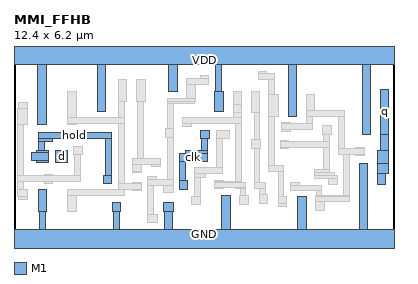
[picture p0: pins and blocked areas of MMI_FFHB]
MACRO MMI_FFHB
	CLASS CORE ;
	FOREIGN MMI_FFHB 0 0 ;
	SIZE 12.4 BY 6.2 ;
	SYMMETRY X Y ;
	SITE CORE1 ;
	PIN d
		DIRECTION input ;
		USE SIGNAL ;
		PORT
			LAYER M1 ;
			RECT 1.36 2.6 1.74 2.98 ;
		END
		AntennaGateArea 0.3465 ;
	END d
	PIN GND
		DIRECTION inout ;
		USE GROUND ;
		PORT
			LAYER M1 ;
			RECT 0.785 1 1.065 1.7 ;
			LAYER M1 ;
			RECT 3.21 1.005 3.49 1.285 ;
			LAYER M1 ;
			RECT 4.875 1.01 5.19 1.29 ;
			LAYER M1 ;
			RECT 0.83 0.42 1.025 1 ;
			LAYER M1 ;
			RECT 3.245 0.42 3.44 1.005 ;
			LAYER M1 ;
			RECT 4.9 0.42 5.18 1.01 ;
			LAYER M1 ;
			RECT 6.78 0.42 7.06 1.53 ;
			LAYER M1 ;
			RECT 9.26 0.42 9.54 1.47 ;
			LAYER M1 ;
			RECT 11.265 0.42 11.545 2.575 ;
			LAYER M1 ;
			RECT 0 -0.42 12.4 0.42 ;
		END
	END GND
	PIN q
		DIRECTION output ;
		USE SIGNAL ;
		PORT
			LAYER M1 ;
			RECT 11.95 3.515 12.23 4.985 ;
			LAYER M1 ;
			RECT 11.955 2.975 12.23 3.515 ;
			LAYER M1 ;
			RECT 11.86 2.575 12.23 2.975 ;
			LAYER M1 ;
			RECT 11.855 2.24 12.23 2.575 ;
			LAYER M1 ;
			RECT 11.855 1.875 12.135 2.24 ;
		END
		AntennaDiffArea 0.91245 ;
	END q
	PIN VDD
		DIRECTION inout ;
		USE POWER ;
		PORT
			LAYER M1 ;
			RECT 0 5.78 12.4 6.62 ;
			LAYER M1 ;
			RECT 0.78 3.845 1.06 5.78 ;
			LAYER M1 ;
			RECT 2.72 4.255 3 5.78 ;
			LAYER M1 ;
			RECT 5.04 4.895 5.32 5.78 ;
			LAYER M1 ;
			RECT 6.59 4.92 6.78 5.78 ;
			LAYER M1 ;
			RECT 6.545 4.25 6.825 4.92 ;
			LAYER M1 ;
			RECT 8.95 4.11 9.23 5.78 ;
			LAYER M1 ;
			RECT 11.36 3.515 11.64 5.78 ;
		END
	END VDD
	PIN clk
		DIRECTION input ;
		USE CLOCK ;
		PORT
			LAYER M1 ;
			RECT 6.085 3.37 6.365 3.65 ;
			LAYER M1 ;
			RECT 6.11 2.99 6.3 3.37 ;
			LAYER M1 ;
			RECT 5.58 2.885 6.3 2.99 ;
			LAYER M1 ;
			RECT 5.39 2.625 6.3 2.885 ;
			LAYER M1 ;
			RECT 5.39 2 5.58 2.625 ;
			LAYER M1 ;
			RECT 5.39 1.72 5.67 2 ;
		END
		AntennaGateArea 0.44625 ;
	END clk
	PIN hold
		DIRECTION input ;
		USE SIGNAL ;
		PORT
			LAYER M1 ;
			RECT 0.795 3.38 3.18 3.575 ;
			LAYER M1 ;
			RECT 0.795 3.295 1.255 3.38 ;
			LAYER M1 ;
			RECT 0.795 2.98 0.99 3.295 ;
			LAYER M1 ;
			RECT 0.735 2.925 1.11 2.98 ;
			LAYER M1 ;
			RECT 0.555 2.645 1.11 2.925 ;
			LAYER M1 ;
			RECT 0.735 2.6 1.11 2.645 ;
			LAYER M1 ;
			RECT 2.99 2.18 3.18 3.38 ;
			LAYER M1 ;
			RECT 2.915 1.9 3.195 2.18 ;
		END
		AntennaGateArea 0.51975 ;
	END hold
	OBS
		LAYER M1 ;
		RECT 0.15 4.365 0.43 4.545 ;
		LAYER M1 ;
		RECT 0.13 3.845 0.43 4.365 ;
		LAYER M1 ;
		RECT 1.755 4.055 2.035 4.91 ;
		LAYER M1 ;
		RECT 3.405 4.59 3.685 5.29 ;
		LAYER M1 ;
		RECT 3.995 4.59 4.275 5.29 ;
		LAYER M1 ;
		RECT 6.08 5.34 6.36 5.43 ;
		LAYER M1 ;
		RECT 5.64 5.15 6.36 5.34 ;
		LAYER M1 ;
		RECT 5.64 4.695 5.92 5.15 ;
		LAYER M1 ;
		RECT 7.965 5.485 8.245 5.575 ;
		LAYER M1 ;
		RECT 7.965 5.295 8.485 5.485 ;
		LAYER M1 ;
		RECT 5 4.59 5.92 4.695 ;
		LAYER M1 ;
		RECT 3.405 4.055 3.595 4.59 ;
		LAYER M1 ;
		RECT 1.755 3.865 3.595 4.055 ;
		LAYER M1 ;
		RECT 1.755 3.85 2.035 3.865 ;
		LAYER M1 ;
		RECT 0.13 2.155 0.325 3.845 ;
		LAYER M1 ;
		RECT 1.95 2.845 2.23 3.125 ;
		LAYER M1 ;
		RECT 0.99 2.155 1.27 2.195 ;
		LAYER M1 ;
		RECT 1.96 2.155 2.155 2.845 ;
		LAYER M1 ;
		RECT 0.13 1.96 2.155 2.155 ;
		LAYER M1 ;
		RECT 0.13 1.7 0.325 1.96 ;
		LAYER M1 ;
		RECT 0.99 1.915 1.27 1.96 ;
		LAYER M1 ;
		RECT 3.405 1.915 3.595 3.865 ;
		LAYER M1 ;
		RECT 4.02 2.725 4.21 4.59 ;
		LAYER M1 ;
		RECT 5 4.505 5.88 4.59 ;
		LAYER M1 ;
		RECT 5 3.695 5.19 4.505 ;
		LAYER M1 ;
		RECT 7.155 4.495 7.435 4.92 ;
		LAYER M1 ;
		RECT 7.15 4.22 7.435 4.495 ;
		LAYER M1 ;
		RECT 7.745 4.22 8.025 4.92 ;
		LAYER M1 ;
		RECT 5.51 4.05 5.79 4.065 ;
		LAYER M1 ;
		RECT 7.15 4.05 7.43 4.22 ;
		LAYER M1 ;
		RECT 5.51 3.855 7.43 4.05 ;
		LAYER M1 ;
		RECT 5.51 3.785 5.79 3.855 ;
		LAYER M1 ;
		RECT 4.94 3.415 5.22 3.695 ;
		LAYER M1 ;
		RECT 4.5 2.725 4.78 2.74 ;
		LAYER M1 ;
		RECT 3.865 2.535 4.78 2.725 ;
		LAYER M1 ;
		RECT 3.865 2.3 4.15 2.535 ;
		LAYER M1 ;
		RECT 4.5 2.46 4.78 2.535 ;
		LAYER M1 ;
		RECT 3.87 2.255 4.15 2.3 ;
		LAYER M1 ;
		RECT 4.365 2.05 4.645 2.14 ;
		LAYER M1 ;
		RECT 5 2.05 5.19 3.415 ;
		LAYER M1 ;
		RECT 6.595 3.37 7.03 3.65 ;
		LAYER M1 ;
		RECT 3.87 1.915 4.15 1.945 ;
		LAYER M1 ;
		RECT 3.405 1.72 4.15 1.915 ;
		LAYER M1 ;
		RECT 3.405 1.7 3.595 1.72 ;
		LAYER M1 ;
		RECT 0.13 1.47 0.43 1.7 ;
		LAYER M1 ;
		RECT 0.15 1.385 0.43 1.47 ;
		LAYER M1 ;
		RECT 1.75 1.51 3.595 1.7 ;
		LAYER M1 ;
		RECT 3.87 1.665 4.15 1.72 ;
		LAYER M1 ;
		RECT 4.365 1.855 5.19 2.05 ;
		LAYER M1 ;
		RECT 1.76 1 2.04 1.51 ;
		LAYER M1 ;
		RECT 4.365 0.905 4.56 1.855 ;
		LAYER M1 ;
		RECT 4.875 1.6 5.19 1.855 ;
		LAYER M1 ;
		RECT 6.595 2.415 6.79 3.37 ;
		LAYER M1 ;
		RECT 5.875 2.22 6.79 2.415 ;
		LAYER M1 ;
		RECT 5.875 2.1 6.24 2.22 ;
		LAYER M1 ;
		RECT 5.875 1.495 6.07 2.1 ;
		LAYER M1 ;
		RECT 6.545 1.975 6.825 2.01 ;
		LAYER M1 ;
		RECT 7.24 1.975 7.43 3.855 ;
		LAYER M1 ;
		RECT 7.835 3.33 8.025 4.22 ;
		LAYER M1 ;
		RECT 8.29 4.81 8.485 5.295 ;
		LAYER M1 ;
		RECT 8.29 4.11 8.64 4.81 ;
		LAYER M1 ;
		RECT 9.54 4.3 9.82 4.81 ;
		LAYER M1 ;
		RECT 9.54 4.11 10.8 4.3 ;
		LAYER M1 ;
		RECT 7.755 3.05 8.035 3.33 ;
		LAYER M1 ;
		RECT 6.545 1.93 7.435 1.975 ;
		LAYER M1 ;
		RECT 7.835 1.94 8.025 3.05 ;
		LAYER M1 ;
		RECT 8.29 2.485 8.485 4.11 ;
		LAYER M1 ;
		RECT 9.545 4.105 10.8 4.11 ;
		LAYER M1 ;
		RECT 8.74 3.87 9.02 3.9 ;
		LAYER M1 ;
		RECT 9.545 3.87 9.74 4.105 ;
		LAYER M1 ;
		RECT 8.74 3.68 9.74 3.87 ;
		LAYER M1 ;
		RECT 8.74 3.62 9.02 3.68 ;
		LAYER M1 ;
		RECT 10.08 3.515 10.36 3.795 ;
		LAYER M1 ;
		RECT 8.69 3.28 8.97 3.325 ;
		LAYER M1 ;
		RECT 10.1 3.28 10.29 3.515 ;
		LAYER M1 ;
		RECT 8.69 3.085 10.29 3.28 ;
		LAYER M1 ;
		RECT 8.69 3.045 8.97 3.085 ;
		LAYER M1 ;
		RECT 8.29 2.29 8.805 2.485 ;
		LAYER M1 ;
		RECT 10.1 2.35 10.29 3.085 ;
		LAYER M1 ;
		RECT 10.605 3.045 10.8 4.105 ;
		LAYER M1 ;
		RECT 11.155 3.045 11.435 3.09 ;
		LAYER M1 ;
		RECT 10.605 2.855 11.435 3.045 ;
		LAYER M1 ;
		RECT 6.545 1.78 7.565 1.93 ;
		LAYER M1 ;
		RECT 6.545 1.73 6.825 1.78 ;
		LAYER M1 ;
		RECT 7.24 1.74 7.565 1.78 ;
		LAYER M1 ;
		RECT 7.835 1.745 8.205 1.94 ;
		LAYER M1 ;
		RECT 7.375 1.53 7.565 1.74 ;
		LAYER M1 ;
		RECT 8.01 1.54 8.205 1.745 ;
		LAYER M1 ;
		RECT 5.78 1.215 6.07 1.495 ;
		LAYER M1 ;
		RECT 4.365 0.625 4.67 0.905 ;
		LAYER M1 ;
		RECT 7.37 1.215 7.65 1.53 ;
		LAYER M1 ;
		RECT 8.005 1.26 8.285 1.54 ;
		LAYER M1 ;
		RECT 8.615 1.47 8.805 2.29 ;
		LAYER M1 ;
		RECT 9.82 2.26 10.29 2.35 ;
		LAYER M1 ;
		RECT 9.82 2.155 10.47 2.26 ;
		LAYER M1 ;
		RECT 9.82 2.07 10.545 2.155 ;
		LAYER M1 ;
		RECT 9.02 1.86 9.3 1.95 ;
		LAYER M1 ;
		RECT 10.265 1.875 10.545 2.07 ;
		LAYER M1 ;
		RECT 9.02 1.67 10.05 1.86 ;
		LAYER M1 ;
		RECT 9.855 1.51 10.05 1.67 ;
		LAYER M1 ;
		RECT 10.745 1.51 10.935 2.855 ;
		LAYER M1 ;
		RECT 11.155 2.81 11.435 2.855 ;
		LAYER M1 ;
		RECT 9.855 1.47 10.935 1.51 ;
		LAYER M1 ;
		RECT 8.615 1.26 8.905 1.47 ;
		LAYER M1 ;
		RECT 8.625 1.155 8.905 1.26 ;
		LAYER M1 ;
		RECT 9.85 1.315 10.935 1.47 ;
		LAYER M1 ;
		RECT 9.85 1.02 10.13 1.315 ;
	END
END MMI_FFHB
